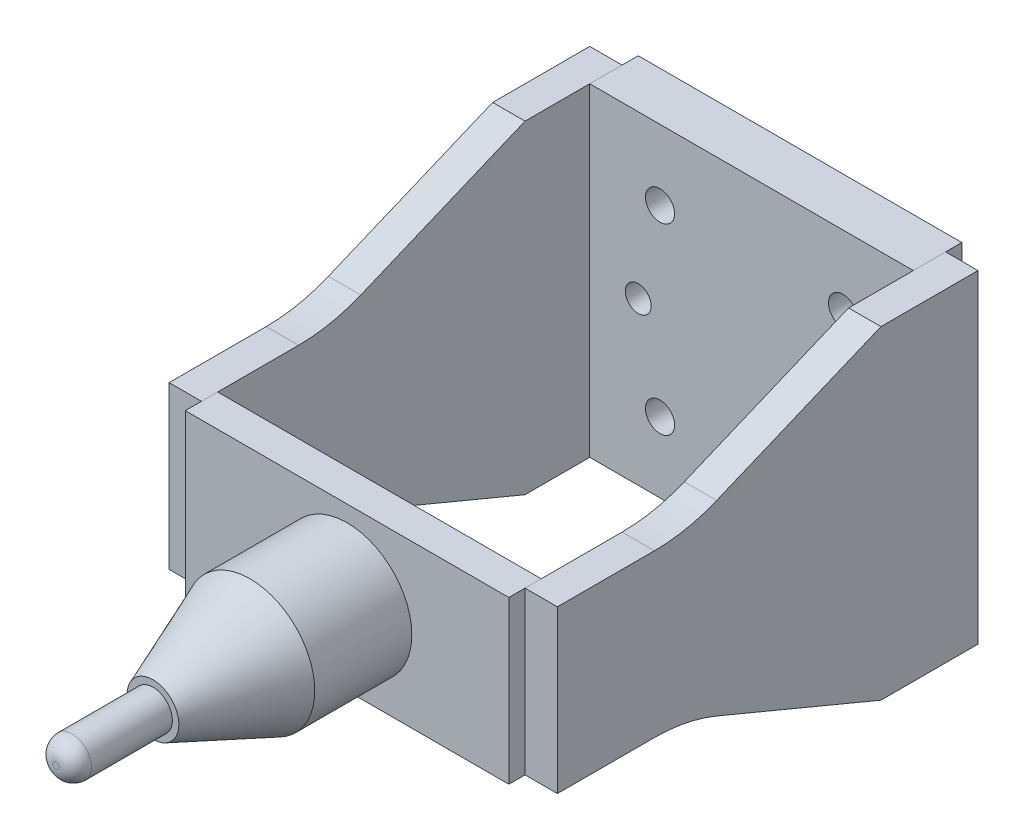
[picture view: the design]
ISO-10303-21;
HEADER;
FILE_DESCRIPTION(('STEP AP214'),'2;1');
FILE_NAME('part.step','',(''),(''),'','','');
FILE_SCHEMA(('AUTOMOTIVE_DESIGN { 1 0 10303 214 1 1 1 1 }'));
ENDSEC;
DATA;
#1=APPLICATION_CONTEXT('core data for automotive mechanical design processes');
#2=APPLICATION_PROTOCOL_DEFINITION('international standard','automotive_design',2000,#1);
#3=PRODUCT_CONTEXT('',#1,'mechanical');
#4=PRODUCT('Part','Part','',(#3));
#5=PRODUCT_RELATED_PRODUCT_CATEGORY('part','',(#4));
#6=PRODUCT_DEFINITION_FORMATION('','',#4);
#7=PRODUCT_DEFINITION_CONTEXT('part definition',#1,'design');
#8=PRODUCT_DEFINITION('design','',#6,#7);
#9=PRODUCT_DEFINITION_SHAPE('','',#8);
#10=(LENGTH_UNIT() NAMED_UNIT(*) SI_UNIT(.MILLI.,.METRE.));
#11=(NAMED_UNIT(*) PLANE_ANGLE_UNIT() SI_UNIT($,.RADIAN.));
#12=(NAMED_UNIT(*) SI_UNIT($,.STERADIAN.) SOLID_ANGLE_UNIT());
#13=UNCERTAINTY_MEASURE_WITH_UNIT(LENGTH_MEASURE(1.E-05),#10,'distance_accuracy_value','');
#14=(GEOMETRIC_REPRESENTATION_CONTEXT(3) GLOBAL_UNCERTAINTY_ASSIGNED_CONTEXT((#13)) GLOBAL_UNIT_ASSIGNED_CONTEXT((#10,
#11,#12)) REPRESENTATION_CONTEXT('',''));
#15=CARTESIAN_POINT('',(0.,0.,0.));
#16=DIRECTION('',(0.,0.,1.));
#17=DIRECTION('',(1.,0.,0.));
#18=AXIS2_PLACEMENT_3D('',#15,#16,#17);
#19=CARTESIAN_POINT('',(0.,0.,230.));
#20=DIRECTION('',(0.,0.,-1.));
#21=DIRECTION('',(-1.,0.,0.));
#22=AXIS2_PLACEMENT_3D('',#19,#20,#21);
#23=CYLINDRICAL_SURFACE('',#22,6.);
#24=CARTESIAN_POINT('',(0.,0.,225.));
#25=DIRECTION('',(0.,0.,1.));
#26=DIRECTION('',(1.,0.,0.));
#27=AXIS2_PLACEMENT_3D('',#24,#25,#26);
#28=CIRCLE('',#27,6.);
#29=CARTESIAN_POINT('',(6.,0.,225.));
#30=VERTEX_POINT('',#29);
#31=EDGE_CURVE('E11',#30,#30,#28,.F.);
#32=ORIENTED_EDGE('',*,*,#31,.T.);
#33=EDGE_LOOP('',(#32));
#34=FACE_BOUND('',#33,.T.);
#35=CARTESIAN_POINT('',(0.,0.,200.));
#36=DIRECTION('',(0.,0.,1.));
#37=DIRECTION('',(1.,0.,0.));
#38=AXIS2_PLACEMENT_3D('',#35,#36,#37);
#39=CIRCLE('',#38,6.);
#40=CARTESIAN_POINT('',(6.,0.,200.));
#41=VERTEX_POINT('',#40);
#42=EDGE_CURVE('E52',#41,#41,#39,.T.);
#43=ORIENTED_EDGE('',*,*,#42,.T.);
#44=EDGE_LOOP('',(#43));
#45=FACE_BOUND('',#44,.T.);
#46=ADVANCED_FACE('F41',(#34,#45),#23,.T.);
#47=CARTESIAN_POINT('',(0.,0.,230.));
#48=DIRECTION('',(0.,0.,1.));
#49=DIRECTION('',(1.,0.,0.));
#50=AXIS2_PLACEMENT_3D('',#47,#48,#49);
#51=PLANE('',#50);
#52=CARTESIAN_POINT('',(0.,0.,230.));
#53=DIRECTION('',(0.,0.,1.));
#54=DIRECTION('',(1.,0.,0.));
#55=AXIS2_PLACEMENT_3D('',#52,#53,#54);
#56=CIRCLE('',#55,1.);
#57=CARTESIAN_POINT('',(1.,0.,230.));
#58=VERTEX_POINT('',#57);
#59=EDGE_CURVE('E48',#58,#58,#56,.T.);
#60=ORIENTED_EDGE('',*,*,#59,.T.);
#61=EDGE_LOOP('',(#60));
#62=FACE_BOUND('',#61,.T.);
#63=ADVANCED_FACE('F62',(#62),#51,.T.);
#64=CARTESIAN_POINT('',(0.,0.,200.));
#65=DIRECTION('',(0.,0.,1.));
#66=DIRECTION('',(1.,0.,0.));
#67=AXIS2_PLACEMENT_3D('',#64,#65,#66);
#68=PLANE('',#67);
#69=ORIENTED_EDGE('',*,*,#42,.F.);
#70=EDGE_LOOP('',(#69));
#71=FACE_BOUND('',#70,.T.);
#72=ADVANCED_FACE('F60',(#71),#68,.F.);
#73=CARTESIAN_POINT('',(0.,0.,225.));
#74=DIRECTION('',(0.,0.,1.));
#75=DIRECTION('',(1.,0.,0.));
#76=AXIS2_PLACEMENT_3D('',#73,#74,#75);
#77=DEGENERATE_TOROIDAL_SURFACE('',#76,1.,5.,.T.);
#78=ORIENTED_EDGE('',*,*,#31,.F.);
#79=EDGE_LOOP('',(#78));
#80=FACE_BOUND('',#79,.T.);
#81=ORIENTED_EDGE('',*,*,#59,.F.);
#82=EDGE_LOOP('',(#81));
#83=FACE_BOUND('',#82,.T.);
#84=ADVANCED_FACE('F43',(#80,#83),#77,.T.);
#85=CLOSED_SHELL('',(#46,#63,#72,#84));
#86=MANIFOLD_SOLID_BREP('B2',#85);
#87=CARTESIAN_POINT('',(0.,0.,140.));
#88=DIRECTION('',(0.,0.,1.));
#89=DIRECTION('',(1.,0.,0.));
#90=AXIS2_PLACEMENT_3D('',#87,#88,#89);
#91=CYLINDRICAL_SURFACE('',#90,20.);
#92=CARTESIAN_POINT('',(0.,0.,170.));
#93=DIRECTION('',(0.,0.,1.));
#94=DIRECTION('',(1.,0.,0.));
#95=AXIS2_PLACEMENT_3D('',#92,#93,#94);
#96=CIRCLE('',#95,20.);
#97=CARTESIAN_POINT('',(20.,0.,170.));
#98=VERTEX_POINT('',#97);
#99=EDGE_CURVE('E127',#98,#98,#96,.T.);
#100=ORIENTED_EDGE('',*,*,#99,.F.);
#101=EDGE_LOOP('',(#100));
#102=FACE_BOUND('',#101,.T.);
#103=CARTESIAN_POINT('',(0.,0.,140.));
#104=DIRECTION('',(0.,0.,1.));
#105=DIRECTION('',(1.,0.,0.));
#106=AXIS2_PLACEMENT_3D('',#103,#104,#105);
#107=CIRCLE('',#106,20.);
#108=CARTESIAN_POINT('',(20.,0.,140.));
#109=VERTEX_POINT('',#108);
#110=EDGE_CURVE('E39',#109,#109,#107,.T.);
#111=ORIENTED_EDGE('',*,*,#110,.T.);
#112=EDGE_LOOP('',(#111));
#113=FACE_BOUND('',#112,.T.);
#114=ADVANCED_FACE('F106',(#102,#113),#91,.T.);
#115=CARTESIAN_POINT('',(0.,20.,140.));
#116=DIRECTION('',(0.,0.,1.));
#117=DIRECTION('',(1.,0.,0.));
#118=AXIS2_PLACEMENT_3D('',#115,#116,#117);
#119=PLANE('',#118);
#120=CARTESIAN_POINT('',(0.,0.,140.));
#121=DIRECTION('',(0.,0.,1.));
#122=DIRECTION('',(1.,0.,0.));
#123=AXIS2_PLACEMENT_3D('',#120,#121,#122);
#124=CIRCLE('',#123,4.99999999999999);
#125=CARTESIAN_POINT('',(4.99999999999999,0.,140.));
#126=VERTEX_POINT('',#125);
#127=EDGE_CURVE('E109',#126,#126,#124,.T.);
#128=ORIENTED_EDGE('',*,*,#127,.T.);
#129=EDGE_LOOP('',(#128));
#130=FACE_BOUND('',#129,.T.);
#131=ORIENTED_EDGE('',*,*,#110,.F.);
#132=EDGE_LOOP('',(#131));
#133=FACE_BOUND('',#132,.T.);
#134=ADVANCED_FACE('F144',(#130,#133),#119,.F.);
#135=CARTESIAN_POINT('',(0.,0.,200.));
#136=DIRECTION('',(0.,0.,-1.));
#137=DIRECTION('',(-1.,0.,0.));
#138=AXIS2_PLACEMENT_3D('',#135,#136,#137);
#139=PLANE('',#138);
#140=CARTESIAN_POINT('',(0.,0.,200.));
#141=DIRECTION('',(0.,0.,1.));
#142=DIRECTION('',(1.,0.,0.));
#143=AXIS2_PLACEMENT_3D('',#140,#141,#142);
#144=CIRCLE('',#143,8.);
#145=CARTESIAN_POINT('',(8.,0.,200.));
#146=VERTEX_POINT('',#145);
#147=EDGE_CURVE('E113',#146,#146,#144,.T.);
#148=ORIENTED_EDGE('',*,*,#147,.T.);
#149=EDGE_LOOP('',(#148));
#150=FACE_BOUND('',#149,.T.);
#151=ADVANCED_FACE('F134',(#150),#139,.F.);
#152=CARTESIAN_POINT('',(0.,0.,170.));
#153=DIRECTION('',(0.,0.,-1.));
#154=DIRECTION('',(-1.,0.,0.));
#155=AXIS2_PLACEMENT_3D('',#152,#153,#154);
#156=CONICAL_SURFACE('',#155,20.,0.380506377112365);
#157=ORIENTED_EDGE('',*,*,#147,.F.);
#158=EDGE_LOOP('',(#157));
#159=FACE_BOUND('',#158,.T.);
#160=ORIENTED_EDGE('',*,*,#99,.T.);
#161=EDGE_LOOP('',(#160));
#162=FACE_BOUND('',#161,.T.);
#163=ADVANCED_FACE('F136',(#159,#162),#156,.T.);
#164=CARTESIAN_POINT('',(0.,0.,130.));
#165=DIRECTION('',(0.,0.,-1.));
#166=DIRECTION('',(-1.,0.,0.));
#167=AXIS2_PLACEMENT_3D('',#164,#165,#166);
#168=CYLINDRICAL_SURFACE('',#167,4.99999999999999);
#169=CARTESIAN_POINT('',(0.,0.,160.));
#170=DIRECTION('',(0.,0.,-1.));
#171=DIRECTION('',(-1.,0.,0.));
#172=AXIS2_PLACEMENT_3D('',#169,#170,#171);
#173=CIRCLE('',#172,4.99999999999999);
#174=CARTESIAN_POINT('',(-4.99999999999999,0.,160.));
#175=VERTEX_POINT('',#174);
#176=EDGE_CURVE('E123',#175,#175,#173,.T.);
#177=ORIENTED_EDGE('',*,*,#176,.F.);
#178=EDGE_LOOP('',(#177));
#179=FACE_BOUND('',#178,.T.);
#180=ORIENTED_EDGE('',*,*,#127,.F.);
#181=EDGE_LOOP('',(#180));
#182=FACE_BOUND('',#181,.T.);
#183=ADVANCED_FACE('F119',(#179,#182),#168,.F.);
#184=CARTESIAN_POINT('',(0.,0.,160.));
#185=DIRECTION('',(0.,0.,-1.));
#186=DIRECTION('',(-1.,0.,0.));
#187=AXIS2_PLACEMENT_3D('',#184,#185,#186);
#188=CONICAL_SURFACE('',#187,4.99999999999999,1.02974425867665);
#189=CARTESIAN_POINT('',(0.,0.,163.004303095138));
#190=VERTEX_POINT('',#189);
#191=VERTEX_LOOP('',#190);
#192=FACE_BOUND('',#191,.T.);
#193=ORIENTED_EDGE('',*,*,#176,.T.);
#194=EDGE_LOOP('',(#193));
#195=FACE_BOUND('',#194,.T.);
#196=ADVANCED_FACE('F116',(#192,#195),#188,.F.);
#197=CLOSED_SHELL('',(#114,#134,#151,#163,#183,#196));
#198=MANIFOLD_SOLID_BREP('B6',#197);
#199=CARTESIAN_POINT('',(-50.,-75.,105.));
#200=DIRECTION('',(-1.,0.,0.));
#201=DIRECTION('',(0.,0.,1.));
#202=AXIS2_PLACEMENT_3D('',#199,#200,#201);
#203=PLANE('',#202);
#204=DIRECTION('',(0.,-1.,0.));
#205=VECTOR('',#204,1.);
#206=CARTESIAN_POINT('',(-50.,25.,140.));
#207=LINE('',#206,#205);
#208=CARTESIAN_POINT('',(-50.,25.,140.));
#209=VERTEX_POINT('',#208);
#210=CARTESIAN_POINT('',(-50.,-25.,140.));
#211=VERTEX_POINT('',#210);
#212=EDGE_CURVE('E211',#209,#211,#207,.T.);
#213=ORIENTED_EDGE('',*,*,#212,.F.);
#214=DIRECTION('',(0.,0.,1.));
#215=VECTOR('',#214,1.);
#216=CARTESIAN_POINT('',(-50.,25.,140.));
#217=LINE('',#216,#215);
#218=CARTESIAN_POINT('',(-50.,25.,130.));
#219=VERTEX_POINT('',#218);
#220=EDGE_CURVE('E256',#219,#209,#217,.T.);
#221=ORIENTED_EDGE('',*,*,#220,.F.);
#222=DIRECTION('',(0.,1.,0.));
#223=VECTOR('',#222,1.);
#224=CARTESIAN_POINT('',(-50.,25.,130.));
#225=LINE('',#224,#223);
#226=CARTESIAN_POINT('',(-50.,-25.,130.));
#227=VERTEX_POINT('',#226);
#228=EDGE_CURVE('E224',#227,#219,#225,.T.);
#229=ORIENTED_EDGE('',*,*,#228,.F.);
#230=DIRECTION('',(0.,0.,-1.));
#231=VECTOR('',#230,1.);
#232=CARTESIAN_POINT('',(-50.,-25.,140.));
#233=LINE('',#232,#231);
#234=EDGE_CURVE('E218',#211,#227,#233,.T.);
#235=ORIENTED_EDGE('',*,*,#234,.F.);
#236=EDGE_LOOP('',(#213,#221,#229,#235));
#237=FACE_BOUND('',#236,.T.);
#238=ADVANCED_FACE('F204',(#237),#203,.T.);
#239=CARTESIAN_POINT('',(-100.990195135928,-25.,140.));
#240=DIRECTION('',(0.,-1.,0.));
#241=DIRECTION('',(0.,0.,-1.));
#242=AXIS2_PLACEMENT_3D('',#239,#240,#241);
#243=PLANE('',#242);
#244=DIRECTION('',(1.,0.,0.));
#245=VECTOR('',#244,1.);
#246=CARTESIAN_POINT('',(-100.990195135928,-25.,140.));
#247=LINE('',#246,#245);
#248=CARTESIAN_POINT('',(50.,-25.,140.));
#249=VERTEX_POINT('',#248);
#250=EDGE_CURVE('E104',#211,#249,#247,.T.);
#251=ORIENTED_EDGE('',*,*,#250,.F.);
#252=ORIENTED_EDGE('',*,*,#234,.T.);
#253=DIRECTION('',(1.,0.,0.));
#254=VECTOR('',#253,1.);
#255=CARTESIAN_POINT('',(-100.990195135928,-25.,130.));
#256=LINE('',#255,#254);
#257=CARTESIAN_POINT('',(50.,-25.,130.));
#258=VERTEX_POINT('',#257);
#259=EDGE_CURVE('E236',#227,#258,#256,.T.);
#260=ORIENTED_EDGE('',*,*,#259,.T.);
#261=DIRECTION('',(0.,0.,1.));
#262=VECTOR('',#261,1.);
#263=CARTESIAN_POINT('',(50.,-25.,140.));
#264=LINE('',#263,#262);
#265=EDGE_CURVE('E263',#258,#249,#264,.T.);
#266=ORIENTED_EDGE('',*,*,#265,.T.);
#267=EDGE_LOOP('',(#251,#252,#260,#266));
#268=FACE_BOUND('',#267,.T.);
#269=ADVANCED_FACE('F280',(#268),#243,.T.);
#270=CARTESIAN_POINT('',(-100.990195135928,25.,130.));
#271=DIRECTION('',(0.,0.,-1.));
#272=DIRECTION('',(-1.,0.,0.));
#273=AXIS2_PLACEMENT_3D('',#270,#271,#272);
#274=PLANE('',#273);
#275=CARTESIAN_POINT('',(0.,0.,130.));
#276=DIRECTION('',(0.,0.,-1.));
#277=DIRECTION('',(-1.,0.,0.));
#278=AXIS2_PLACEMENT_3D('',#275,#276,#277);
#279=CIRCLE('',#278,5.);
#280=CARTESIAN_POINT('',(-5.,0.,130.));
#281=VERTEX_POINT('',#280);
#282=EDGE_CURVE('E269',#281,#281,#279,.T.);
#283=ORIENTED_EDGE('',*,*,#282,.F.);
#284=EDGE_LOOP('',(#283));
#285=FACE_BOUND('',#284,.T.);
#286=ORIENTED_EDGE('',*,*,#259,.F.);
#287=ORIENTED_EDGE('',*,*,#228,.T.);
#288=DIRECTION('',(1.,0.,0.));
#289=VECTOR('',#288,1.);
#290=CARTESIAN_POINT('',(-100.990195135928,25.,130.));
#291=LINE('',#290,#289);
#292=CARTESIAN_POINT('',(50.,25.,130.));
#293=VERTEX_POINT('',#292);
#294=EDGE_CURVE('E252',#219,#293,#291,.T.);
#295=ORIENTED_EDGE('',*,*,#294,.T.);
#296=DIRECTION('',(0.,-1.,0.));
#297=VECTOR('',#296,1.);
#298=CARTESIAN_POINT('',(50.,25.,130.));
#299=LINE('',#298,#297);
#300=EDGE_CURVE('E255',#293,#258,#299,.T.);
#301=ORIENTED_EDGE('',*,*,#300,.T.);
#302=EDGE_LOOP('',(#286,#287,#295,#301));
#303=FACE_BOUND('',#302,.T.);
#304=ADVANCED_FACE('F254',(#285,#303),#274,.T.);
#305=CARTESIAN_POINT('',(-100.990195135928,25.,140.));
#306=DIRECTION('',(0.,1.,0.));
#307=DIRECTION('',(0.,0.,1.));
#308=AXIS2_PLACEMENT_3D('',#305,#306,#307);
#309=PLANE('',#308);
#310=ORIENTED_EDGE('',*,*,#294,.F.);
#311=ORIENTED_EDGE('',*,*,#220,.T.);
#312=DIRECTION('',(1.,0.,0.));
#313=VECTOR('',#312,1.);
#314=CARTESIAN_POINT('',(-100.990195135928,25.,140.));
#315=LINE('',#314,#313);
#316=CARTESIAN_POINT('',(50.,25.,140.));
#317=VERTEX_POINT('',#316);
#318=EDGE_CURVE('E243',#209,#317,#315,.T.);
#319=ORIENTED_EDGE('',*,*,#318,.T.);
#320=DIRECTION('',(0.,0.,-1.));
#321=VECTOR('',#320,1.);
#322=CARTESIAN_POINT('',(50.,25.,140.));
#323=LINE('',#322,#321);
#324=EDGE_CURVE('E261',#317,#293,#323,.T.);
#325=ORIENTED_EDGE('',*,*,#324,.T.);
#326=EDGE_LOOP('',(#310,#311,#319,#325));
#327=FACE_BOUND('',#326,.T.);
#328=ADVANCED_FACE('F265',(#327),#309,.T.);
#329=CARTESIAN_POINT('',(-100.990195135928,25.,140.));
#330=DIRECTION('',(0.,0.,1.));
#331=DIRECTION('',(1.,0.,0.));
#332=AXIS2_PLACEMENT_3D('',#329,#330,#331);
#333=PLANE('',#332);
#334=CARTESIAN_POINT('',(0.,0.,140.));
#335=DIRECTION('',(0.,0.,1.));
#336=DIRECTION('',(1.,0.,0.));
#337=AXIS2_PLACEMENT_3D('',#334,#335,#336);
#338=CIRCLE('',#337,4.99999999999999);
#339=CARTESIAN_POINT('',(4.99999999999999,0.,140.));
#340=VERTEX_POINT('',#339);
#341=EDGE_CURVE('E266',#340,#340,#338,.T.);
#342=ORIENTED_EDGE('',*,*,#341,.F.);
#343=EDGE_LOOP('',(#342));
#344=FACE_BOUND('',#343,.T.);
#345=ORIENTED_EDGE('',*,*,#318,.F.);
#346=ORIENTED_EDGE('',*,*,#212,.T.);
#347=ORIENTED_EDGE('',*,*,#250,.T.);
#348=DIRECTION('',(0.,1.,0.));
#349=VECTOR('',#348,1.);
#350=CARTESIAN_POINT('',(50.,25.,140.));
#351=LINE('',#350,#349);
#352=EDGE_CURVE('E273',#249,#317,#351,.T.);
#353=ORIENTED_EDGE('',*,*,#352,.T.);
#354=EDGE_LOOP('',(#345,#346,#347,#353));
#355=FACE_BOUND('',#354,.T.);
#356=ADVANCED_FACE('F293',(#344,#355),#333,.T.);
#357=CARTESIAN_POINT('',(50.,0.,0.));
#358=DIRECTION('',(-1.,0.,0.));
#359=DIRECTION('',(0.,0.,1.));
#360=AXIS2_PLACEMENT_3D('',#357,#358,#359);
#361=PLANE('',#360);
#362=ORIENTED_EDGE('',*,*,#265,.F.);
#363=ORIENTED_EDGE('',*,*,#300,.F.);
#364=ORIENTED_EDGE('',*,*,#324,.F.);
#365=ORIENTED_EDGE('',*,*,#352,.F.);
#366=EDGE_LOOP('',(#362,#363,#364,#365));
#367=FACE_BOUND('',#366,.T.);
#368=ADVANCED_FACE('F259',(#367),#361,.F.);
#369=CARTESIAN_POINT('',(0.,0.,130.));
#370=DIRECTION('',(0.,0.,-1.));
#371=DIRECTION('',(-1.,0.,0.));
#372=AXIS2_PLACEMENT_3D('',#369,#370,#371);
#373=CYLINDRICAL_SURFACE('',#372,4.99999999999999);
#374=ORIENTED_EDGE('',*,*,#341,.T.);
#375=EDGE_LOOP('',(#374));
#376=FACE_BOUND('',#375,.T.);
#377=ORIENTED_EDGE('',*,*,#282,.T.);
#378=EDGE_LOOP('',(#377));
#379=FACE_BOUND('',#378,.T.);
#380=ADVANCED_FACE('F299',(#376,#379),#373,.F.);
#381=CLOSED_SHELL('',(#238,#269,#304,#328,#356,#368,#380));
#382=MANIFOLD_SOLID_BREP('B33',#381);
#383=CARTESIAN_POINT('',(-60.,28.8461538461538,85.7692307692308));
#384=DIRECTION('',(0.,-0.923076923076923,-0.384615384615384));
#385=DIRECTION('',(0.,0.384615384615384,-0.923076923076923));
#386=AXIS2_PLACEMENT_3D('',#383,#384,#385);
#387=PLANE('',#386);
#388=DIRECTION('',(0.,0.384615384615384,-0.923076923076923));
#389=VECTOR('',#388,1.);
#390=CARTESIAN_POINT('',(-50.,28.8461538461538,85.7692307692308));
#391=LINE('',#390,#389);
#392=CARTESIAN_POINT('',(-50.,28.8461538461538,85.7692307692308));
#393=VERTEX_POINT('',#392);
#394=CARTESIAN_POINT('',(-50.,50.,35.));
#395=VERTEX_POINT('',#394);
#396=EDGE_CURVE('E466',#393,#395,#391,.T.);
#397=ORIENTED_EDGE('',*,*,#396,.T.);
#398=DIRECTION('',(1.,0.,0.));
#399=VECTOR('',#398,1.);
#400=CARTESIAN_POINT('',(-60.,50.,35.));
#401=LINE('',#400,#399);
#402=CARTESIAN_POINT('',(-60.,50.,35.));
#403=VERTEX_POINT('',#402);
#404=EDGE_CURVE('E202',#403,#395,#401,.T.);
#405=ORIENTED_EDGE('',*,*,#404,.F.);
#406=DIRECTION('',(0.,0.384615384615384,-0.923076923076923));
#407=VECTOR('',#406,1.);
#408=CARTESIAN_POINT('',(-60.,28.8461538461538,85.7692307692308));
#409=LINE('',#408,#407);
#410=CARTESIAN_POINT('',(-60.,28.8461538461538,85.7692307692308));
#411=VERTEX_POINT('',#410);
#412=EDGE_CURVE('E484',#411,#403,#409,.T.);
#413=ORIENTED_EDGE('',*,*,#412,.F.);
#414=DIRECTION('',(1.,0.,0.));
#415=VECTOR('',#414,1.);
#416=CARTESIAN_POINT('',(-60.,28.8461538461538,85.7692307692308));
#417=LINE('',#416,#415);
#418=EDGE_CURVE('E462',#411,#393,#417,.T.);
#419=ORIENTED_EDGE('',*,*,#418,.T.);
#420=EDGE_LOOP('',(#397,#405,#413,#419));
#421=FACE_BOUND('',#420,.T.);
#422=ADVANCED_FACE('F358',(#421),#387,.F.);
#423=CARTESIAN_POINT('',(-60.,50.,35.));
#424=DIRECTION('',(0.,-1.,0.));
#425=DIRECTION('',(0.,0.,-1.));
#426=AXIS2_PLACEMENT_3D('',#423,#424,#425);
#427=PLANE('',#426);
#428=DIRECTION('',(0.,0.,-1.));
#429=VECTOR('',#428,1.);
#430=CARTESIAN_POINT('',(-50.,50.,35.));
#431=LINE('',#430,#429);
#432=CARTESIAN_POINT('',(-50.,50.,4.99999999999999));
#433=VERTEX_POINT('',#432);
#434=EDGE_CURVE('E469',#395,#433,#431,.T.);
#435=ORIENTED_EDGE('',*,*,#434,.T.);
#436=DIRECTION('',(1.,0.,0.));
#437=VECTOR('',#436,1.);
#438=CARTESIAN_POINT('',(-60.,50.,4.99999999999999));
#439=LINE('',#438,#437);
#440=CARTESIAN_POINT('',(-60.,50.,4.99999999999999));
#441=VERTEX_POINT('',#440);
#442=EDGE_CURVE('E366',#441,#433,#439,.T.);
#443=ORIENTED_EDGE('',*,*,#442,.F.);
#444=DIRECTION('',(0.,0.,-1.));
#445=VECTOR('',#444,1.);
#446=CARTESIAN_POINT('',(-60.,50.,35.));
#447=LINE('',#446,#445);
#448=EDGE_CURVE('E423',#403,#441,#447,.T.);
#449=ORIENTED_EDGE('',*,*,#448,.F.);
#450=ORIENTED_EDGE('',*,*,#404,.T.);
#451=EDGE_LOOP('',(#435,#443,#449,#450));
#452=FACE_BOUND('',#451,.T.);
#453=ADVANCED_FACE('F533',(#452),#427,.F.);
#454=CARTESIAN_POINT('',(-60.,50.,4.99999999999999));
#455=DIRECTION('',(0.,0.,1.));
#456=DIRECTION('',(0.,-1.,0.));
#457=AXIS2_PLACEMENT_3D('',#454,#455,#456);
#458=PLANE('',#457);
#459=DIRECTION('',(0.,-1.,0.));
#460=VECTOR('',#459,1.);
#461=CARTESIAN_POINT('',(-50.,50.,4.99999999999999));
#462=LINE('',#461,#460);
#463=CARTESIAN_POINT('',(-50.,-50.,4.99999999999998));
#464=VERTEX_POINT('',#463);
#465=EDGE_CURVE('E471',#433,#464,#462,.T.);
#466=ORIENTED_EDGE('',*,*,#465,.T.);
#467=DIRECTION('',(1.,0.,0.));
#468=VECTOR('',#467,1.);
#469=CARTESIAN_POINT('',(-60.,-50.,4.99999999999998));
#470=LINE('',#469,#468);
#471=CARTESIAN_POINT('',(-60.,-50.,4.99999999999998));
#472=VERTEX_POINT('',#471);
#473=EDGE_CURVE('E497',#472,#464,#470,.T.);
#474=ORIENTED_EDGE('',*,*,#473,.F.);
#475=DIRECTION('',(0.,-1.,0.));
#476=VECTOR('',#475,1.);
#477=CARTESIAN_POINT('',(-60.,50.,4.99999999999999));
#478=LINE('',#477,#476);
#479=EDGE_CURVE('E505',#441,#472,#478,.T.);
#480=ORIENTED_EDGE('',*,*,#479,.F.);
#481=ORIENTED_EDGE('',*,*,#442,.T.);
#482=EDGE_LOOP('',(#466,#474,#480,#481));
#483=FACE_BOUND('',#482,.T.);
#484=ADVANCED_FACE('F503',(#483),#458,.F.);
#485=CARTESIAN_POINT('',(-60.,-50.,4.99999999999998));
#486=DIRECTION('',(0.,1.,0.));
#487=DIRECTION('',(0.,0.,1.));
#488=AXIS2_PLACEMENT_3D('',#485,#486,#487);
#489=PLANE('',#488);
#490=DIRECTION('',(0.,0.,1.));
#491=VECTOR('',#490,1.);
#492=CARTESIAN_POINT('',(-50.,-50.,4.99999999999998));
#493=LINE('',#492,#491);
#494=CARTESIAN_POINT('',(-50.,-50.,35.));
#495=VERTEX_POINT('',#494);
#496=EDGE_CURVE('E473',#464,#495,#493,.T.);
#497=ORIENTED_EDGE('',*,*,#496,.T.);
#498=DIRECTION('',(1.,0.,0.));
#499=VECTOR('',#498,1.);
#500=CARTESIAN_POINT('',(-60.,-50.,35.));
#501=LINE('',#500,#499);
#502=CARTESIAN_POINT('',(-60.,-50.,35.));
#503=VERTEX_POINT('',#502);
#504=EDGE_CURVE('E494',#503,#495,#501,.T.);
#505=ORIENTED_EDGE('',*,*,#504,.F.);
#506=DIRECTION('',(0.,0.,1.));
#507=VECTOR('',#506,1.);
#508=CARTESIAN_POINT('',(-60.,-50.,4.99999999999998));
#509=LINE('',#508,#507);
#510=EDGE_CURVE('E523',#472,#503,#509,.T.);
#511=ORIENTED_EDGE('',*,*,#510,.F.);
#512=ORIENTED_EDGE('',*,*,#473,.T.);
#513=EDGE_LOOP('',(#497,#505,#511,#512));
#514=FACE_BOUND('',#513,.T.);
#515=ADVANCED_FACE('F514',(#514),#489,.F.);
#516=CARTESIAN_POINT('',(-60.,-50.,35.));
#517=DIRECTION('',(0.,0.923076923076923,-0.384615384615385));
#518=DIRECTION('',(0.,0.384615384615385,0.923076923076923));
#519=AXIS2_PLACEMENT_3D('',#516,#517,#518);
#520=PLANE('',#519);
#521=DIRECTION('',(0.,0.384615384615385,0.923076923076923));
#522=VECTOR('',#521,1.);
#523=CARTESIAN_POINT('',(-50.,-50.,35.));
#524=LINE('',#523,#522);
#525=CARTESIAN_POINT('',(-50.,-28.8461538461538,85.7692307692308));
#526=VERTEX_POINT('',#525);
#527=EDGE_CURVE('E475',#495,#526,#524,.T.);
#528=ORIENTED_EDGE('',*,*,#527,.T.);
#529=DIRECTION('',(1.,0.,0.));
#530=VECTOR('',#529,1.);
#531=CARTESIAN_POINT('',(-60.,-28.8461538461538,85.7692307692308));
#532=LINE('',#531,#530);
#533=CARTESIAN_POINT('',(-60.,-28.8461538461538,85.7692307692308));
#534=VERTEX_POINT('',#533);
#535=EDGE_CURVE('E491',#534,#526,#532,.T.);
#536=ORIENTED_EDGE('',*,*,#535,.F.);
#537=DIRECTION('',(0.,0.384615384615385,0.923076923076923));
#538=VECTOR('',#537,1.);
#539=CARTESIAN_POINT('',(-60.,-50.,35.));
#540=LINE('',#539,#538);
#541=EDGE_CURVE('E520',#503,#534,#540,.T.);
#542=ORIENTED_EDGE('',*,*,#541,.F.);
#543=ORIENTED_EDGE('',*,*,#504,.T.);
#544=EDGE_LOOP('',(#528,#536,#542,#543));
#545=FACE_BOUND('',#544,.T.);
#546=ADVANCED_FACE('F518',(#545),#520,.F.);
#547=CARTESIAN_POINT('',(-60.,-75.,105.));
#548=DIRECTION('',(1.,0.,0.));
#549=DIRECTION('',(0.,0.,-1.));
#550=AXIS2_PLACEMENT_3D('',#547,#548,#549);
#551=CYLINDRICAL_SURFACE('',#550,50.);
#552=CARTESIAN_POINT('',(-50.,-75.,105.));
#553=DIRECTION('',(1.,0.,0.));
#554=DIRECTION('',(0.,0.,1.));
#555=AXIS2_PLACEMENT_3D('',#552,#553,#554);
#556=CIRCLE('',#555,50.);
#557=CARTESIAN_POINT('',(-50.,-25.,105.));
#558=VERTEX_POINT('',#557);
#559=EDGE_CURVE('E477',#526,#558,#556,.T.);
#560=ORIENTED_EDGE('',*,*,#559,.T.);
#561=DIRECTION('',(1.,0.,0.));
#562=VECTOR('',#561,1.);
#563=CARTESIAN_POINT('',(-60.,-25.,105.));
#564=LINE('',#563,#562);
#565=CARTESIAN_POINT('',(-60.,-25.,105.));
#566=VERTEX_POINT('',#565);
#567=EDGE_CURVE('E488',#566,#558,#564,.T.);
#568=ORIENTED_EDGE('',*,*,#567,.F.);
#569=CARTESIAN_POINT('',(-60.,-75.,105.));
#570=DIRECTION('',(1.,0.,0.));
#571=DIRECTION('',(0.,0.,1.));
#572=AXIS2_PLACEMENT_3D('',#569,#570,#571);
#573=CIRCLE('',#572,50.);
#574=EDGE_CURVE('E522',#534,#566,#573,.T.);
#575=ORIENTED_EDGE('',*,*,#574,.F.);
#576=ORIENTED_EDGE('',*,*,#535,.T.);
#577=EDGE_LOOP('',(#560,#568,#575,#576));
#578=FACE_BOUND('',#577,.T.);
#579=ADVANCED_FACE('F545',(#578),#551,.F.);
#580=CARTESIAN_POINT('',(-60.,-25.,105.));
#581=DIRECTION('',(0.,1.,0.));
#582=DIRECTION('',(0.,0.,1.));
#583=AXIS2_PLACEMENT_3D('',#580,#581,#582);
#584=PLANE('',#583);
#585=DIRECTION('',(0.,0.,1.));
#586=VECTOR('',#585,1.);
#587=CARTESIAN_POINT('',(-50.,-25.,105.));
#588=LINE('',#587,#586);
#589=CARTESIAN_POINT('',(-50.,-25.,135.));
#590=VERTEX_POINT('',#589);
#591=EDGE_CURVE('E479',#558,#590,#588,.T.);
#592=ORIENTED_EDGE('',*,*,#591,.T.);
#593=DIRECTION('',(1.,0.,0.));
#594=VECTOR('',#593,1.);
#595=CARTESIAN_POINT('',(-60.,-25.,135.));
#596=LINE('',#595,#594);
#597=CARTESIAN_POINT('',(-60.,-25.,135.));
#598=VERTEX_POINT('',#597);
#599=EDGE_CURVE('E457',#598,#590,#596,.T.);
#600=ORIENTED_EDGE('',*,*,#599,.F.);
#601=DIRECTION('',(0.,0.,1.));
#602=VECTOR('',#601,1.);
#603=CARTESIAN_POINT('',(-60.,-25.,105.));
#604=LINE('',#603,#602);
#605=EDGE_CURVE('E448',#566,#598,#604,.T.);
#606=ORIENTED_EDGE('',*,*,#605,.F.);
#607=ORIENTED_EDGE('',*,*,#567,.T.);
#608=EDGE_LOOP('',(#592,#600,#606,#607));
#609=FACE_BOUND('',#608,.T.);
#610=ADVANCED_FACE('F548',(#609),#584,.F.);
#611=CARTESIAN_POINT('',(-60.,-25.,135.));
#612=DIRECTION('',(0.,0.,-1.));
#613=DIRECTION('',(-1.,0.,0.));
#614=AXIS2_PLACEMENT_3D('',#611,#612,#613);
#615=PLANE('',#614);
#616=DIRECTION('',(0.,1.,0.));
#617=VECTOR('',#616,1.);
#618=CARTESIAN_POINT('',(-50.,-25.,135.));
#619=LINE('',#618,#617);
#620=CARTESIAN_POINT('',(-50.,25.,135.));
#621=VERTEX_POINT('',#620);
#622=EDGE_CURVE('E456',#590,#621,#619,.T.);
#623=ORIENTED_EDGE('',*,*,#622,.T.);
#624=DIRECTION('',(1.,0.,0.));
#625=VECTOR('',#624,1.);
#626=CARTESIAN_POINT('',(-60.,25.,135.));
#627=LINE('',#626,#625);
#628=CARTESIAN_POINT('',(-60.,25.,135.));
#629=VERTEX_POINT('',#628);
#630=EDGE_CURVE('E453',#629,#621,#627,.T.);
#631=ORIENTED_EDGE('',*,*,#630,.F.);
#632=DIRECTION('',(0.,1.,0.));
#633=VECTOR('',#632,1.);
#634=CARTESIAN_POINT('',(-60.,-25.,135.));
#635=LINE('',#634,#633);
#636=EDGE_CURVE('E442',#598,#629,#635,.T.);
#637=ORIENTED_EDGE('',*,*,#636,.F.);
#638=ORIENTED_EDGE('',*,*,#599,.T.);
#639=EDGE_LOOP('',(#623,#631,#637,#638));
#640=FACE_BOUND('',#639,.T.);
#641=ADVANCED_FACE('F454',(#640),#615,.F.);
#642=CARTESIAN_POINT('',(-60.,25.,135.));
#643=DIRECTION('',(0.,-1.,0.));
#644=DIRECTION('',(0.,0.,-1.));
#645=AXIS2_PLACEMENT_3D('',#642,#643,#644);
#646=PLANE('',#645);
#647=DIRECTION('',(0.,0.,-1.));
#648=VECTOR('',#647,1.);
#649=CARTESIAN_POINT('',(-50.,25.,135.));
#650=LINE('',#649,#648);
#651=CARTESIAN_POINT('',(-50.,25.,105.));
#652=VERTEX_POINT('',#651);
#653=EDGE_CURVE('E409',#621,#652,#650,.T.);
#654=ORIENTED_EDGE('',*,*,#653,.T.);
#655=DIRECTION('',(1.,0.,0.));
#656=VECTOR('',#655,1.);
#657=CARTESIAN_POINT('',(-60.,25.,105.));
#658=LINE('',#657,#656);
#659=CARTESIAN_POINT('',(-60.,25.,105.));
#660=VERTEX_POINT('',#659);
#661=EDGE_CURVE('E458',#660,#652,#658,.T.);
#662=ORIENTED_EDGE('',*,*,#661,.F.);
#663=DIRECTION('',(0.,0.,-1.));
#664=VECTOR('',#663,1.);
#665=CARTESIAN_POINT('',(-60.,25.,135.));
#666=LINE('',#665,#664);
#667=EDGE_CURVE('E446',#629,#660,#666,.T.);
#668=ORIENTED_EDGE('',*,*,#667,.F.);
#669=ORIENTED_EDGE('',*,*,#630,.T.);
#670=EDGE_LOOP('',(#654,#662,#668,#669));
#671=FACE_BOUND('',#670,.T.);
#672=ADVANCED_FACE('F460',(#671),#646,.F.);
#673=CARTESIAN_POINT('',(-60.,75.,105.));
#674=DIRECTION('',(1.,0.,0.));
#675=DIRECTION('',(0.,0.,-1.));
#676=AXIS2_PLACEMENT_3D('',#673,#674,#675);
#677=CYLINDRICAL_SURFACE('',#676,50.);
#678=CARTESIAN_POINT('',(-50.,75.,105.));
#679=DIRECTION('',(1.,0.,0.));
#680=DIRECTION('',(0.,0.,1.));
#681=AXIS2_PLACEMENT_3D('',#678,#679,#680);
#682=CIRCLE('',#681,50.);
#683=EDGE_CURVE('E415',#652,#393,#682,.T.);
#684=ORIENTED_EDGE('',*,*,#683,.T.);
#685=ORIENTED_EDGE('',*,*,#418,.F.);
#686=CARTESIAN_POINT('',(-60.,75.,105.));
#687=DIRECTION('',(1.,0.,0.));
#688=DIRECTION('',(0.,0.,1.));
#689=AXIS2_PLACEMENT_3D('',#686,#687,#688);
#690=CIRCLE('',#689,50.);
#691=EDGE_CURVE('E374',#660,#411,#690,.T.);
#692=ORIENTED_EDGE('',*,*,#691,.F.);
#693=ORIENTED_EDGE('',*,*,#661,.T.);
#694=EDGE_LOOP('',(#684,#685,#692,#693));
#695=FACE_BOUND('',#694,.T.);
#696=ADVANCED_FACE('F557',(#695),#677,.F.);
#697=CARTESIAN_POINT('',(-60.,-75.,105.));
#698=DIRECTION('',(-1.,0.,0.));
#699=DIRECTION('',(0.,0.,1.));
#700=AXIS2_PLACEMENT_3D('',#697,#698,#699);
#701=PLANE('',#700);
#702=ORIENTED_EDGE('',*,*,#412,.T.);
#703=ORIENTED_EDGE('',*,*,#448,.T.);
#704=ORIENTED_EDGE('',*,*,#479,.T.);
#705=ORIENTED_EDGE('',*,*,#510,.T.);
#706=ORIENTED_EDGE('',*,*,#541,.T.);
#707=ORIENTED_EDGE('',*,*,#574,.T.);
#708=ORIENTED_EDGE('',*,*,#605,.T.);
#709=ORIENTED_EDGE('',*,*,#636,.T.);
#710=ORIENTED_EDGE('',*,*,#667,.T.);
#711=ORIENTED_EDGE('',*,*,#691,.T.);
#712=EDGE_LOOP('',(#702,#703,#704,#705,#706,#707,#708,#709,#710,#711));
#713=FACE_BOUND('',#712,.T.);
#714=ADVANCED_FACE('F444',(#713),#701,.T.);
#715=CARTESIAN_POINT('',(-50.,-75.,105.));
#716=DIRECTION('',(-1.,0.,0.));
#717=DIRECTION('',(0.,0.,1.));
#718=AXIS2_PLACEMENT_3D('',#715,#716,#717);
#719=PLANE('',#718);
#720=ORIENTED_EDGE('',*,*,#396,.F.);
#721=ORIENTED_EDGE('',*,*,#683,.F.);
#722=ORIENTED_EDGE('',*,*,#653,.F.);
#723=ORIENTED_EDGE('',*,*,#622,.F.);
#724=ORIENTED_EDGE('',*,*,#591,.F.);
#725=ORIENTED_EDGE('',*,*,#559,.F.);
#726=ORIENTED_EDGE('',*,*,#527,.F.);
#727=ORIENTED_EDGE('',*,*,#496,.F.);
#728=ORIENTED_EDGE('',*,*,#465,.F.);
#729=ORIENTED_EDGE('',*,*,#434,.F.);
#730=EDGE_LOOP('',(#720,#721,#722,#723,#724,#725,#726,#727,#728,#729));
#731=FACE_BOUND('',#730,.T.);
#732=ADVANCED_FACE('F509',(#731),#719,.F.);
#733=CLOSED_SHELL('',(#422,#453,#484,#515,#546,#579,#610,#641,#672,#696,#714,#732));
#734=MANIFOLD_SOLID_BREP('B98',#733);
#735=CARTESIAN_POINT('',(60.,50.,35.));
#736=DIRECTION('',(0.,-1.,0.));
#737=DIRECTION('',(0.,0.,-1.));
#738=AXIS2_PLACEMENT_3D('',#735,#736,#737);
#739=PLANE('',#738);
#740=DIRECTION('',(0.,0.,1.));
#741=VECTOR('',#740,1.);
#742=CARTESIAN_POINT('',(50.,50.,35.));
#743=LINE('',#742,#741);
#744=CARTESIAN_POINT('',(50.,50.,4.99999999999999));
#745=VERTEX_POINT('',#744);
#746=CARTESIAN_POINT('',(50.,50.,35.));
#747=VERTEX_POINT('',#746);
#748=EDGE_CURVE('E740',#745,#747,#743,.T.);
#749=ORIENTED_EDGE('',*,*,#748,.T.);
#750=DIRECTION('',(-1.,0.,0.));
#751=VECTOR('',#750,1.);
#752=CARTESIAN_POINT('',(60.,50.,35.));
#753=LINE('',#752,#751);
#754=CARTESIAN_POINT('',(60.,50.,35.));
#755=VERTEX_POINT('',#754);
#756=EDGE_CURVE('E723',#755,#747,#753,.T.);
#757=ORIENTED_EDGE('',*,*,#756,.F.);
#758=DIRECTION('',(0.,0.,1.));
#759=VECTOR('',#758,1.);
#760=CARTESIAN_POINT('',(60.,50.,35.));
#761=LINE('',#760,#759);
#762=CARTESIAN_POINT('',(60.,50.,4.99999999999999));
#763=VERTEX_POINT('',#762);
#764=EDGE_CURVE('E728',#763,#755,#761,.T.);
#765=ORIENTED_EDGE('',*,*,#764,.F.);
#766=DIRECTION('',(-1.,0.,0.));
#767=VECTOR('',#766,1.);
#768=CARTESIAN_POINT('',(60.,50.,4.99999999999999));
#769=LINE('',#768,#767);
#770=EDGE_CURVE('E800',#763,#745,#769,.T.);
#771=ORIENTED_EDGE('',*,*,#770,.T.);
#772=EDGE_LOOP('',(#749,#757,#765,#771));
#773=FACE_BOUND('',#772,.T.);
#774=ADVANCED_FACE('F646',(#773),#739,.F.);
#775=CARTESIAN_POINT('',(60.,25.,95.));
#776=DIRECTION('',(0.,-0.923076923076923,-0.384615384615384));
#777=DIRECTION('',(0.,0.384615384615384,-0.923076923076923));
#778=AXIS2_PLACEMENT_3D('',#775,#776,#777);
#779=PLANE('',#778);
#780=DIRECTION('',(0.,-0.384615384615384,0.923076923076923));
#781=VECTOR('',#780,1.);
#782=CARTESIAN_POINT('',(50.,25.,95.));
#783=LINE('',#782,#781);
#784=CARTESIAN_POINT('',(50.,28.8461538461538,85.7692307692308));
#785=VERTEX_POINT('',#784);
#786=EDGE_CURVE('E815',#747,#785,#783,.T.);
#787=ORIENTED_EDGE('',*,*,#786,.T.);
#788=DIRECTION('',(-1.,0.,0.));
#789=VECTOR('',#788,1.);
#790=CARTESIAN_POINT('',(60.,28.8461538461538,85.7692307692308));
#791=LINE('',#790,#789);
#792=CARTESIAN_POINT('',(60.,28.8461538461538,85.7692307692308));
#793=VERTEX_POINT('',#792);
#794=EDGE_CURVE('E661',#785,#793,#791,.F.);
#795=ORIENTED_EDGE('',*,*,#794,.T.);
#796=DIRECTION('',(0.,-0.384615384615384,0.923076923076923));
#797=VECTOR('',#796,1.);
#798=CARTESIAN_POINT('',(60.,25.,95.));
#799=LINE('',#798,#797);
#800=EDGE_CURVE('E719',#755,#793,#799,.T.);
#801=ORIENTED_EDGE('',*,*,#800,.F.);
#802=ORIENTED_EDGE('',*,*,#756,.T.);
#803=EDGE_LOOP('',(#787,#795,#801,#802));
#804=FACE_BOUND('',#803,.T.);
#805=ADVANCED_FACE('F721',(#804),#779,.F.);
#806=CARTESIAN_POINT('',(60.,25.,135.));
#807=DIRECTION('',(0.,-1.,0.));
#808=DIRECTION('',(0.,0.,-1.));
#809=AXIS2_PLACEMENT_3D('',#806,#807,#808);
#810=PLANE('',#809);
#811=DIRECTION('',(0.,0.,1.));
#812=VECTOR('',#811,1.);
#813=CARTESIAN_POINT('',(60.,25.,135.));
#814=LINE('',#813,#812);
#815=CARTESIAN_POINT('',(60.,25.,105.));
#816=VERTEX_POINT('',#815);
#817=CARTESIAN_POINT('',(60.,25.,135.));
#818=VERTEX_POINT('',#817);
#819=EDGE_CURVE('E727',#816,#818,#814,.T.);
#820=ORIENTED_EDGE('',*,*,#819,.F.);
#821=DIRECTION('',(-1.,0.,0.));
#822=VECTOR('',#821,1.);
#823=CARTESIAN_POINT('',(50.,25.,105.));
#824=LINE('',#823,#822);
#825=CARTESIAN_POINT('',(50.,25.,105.));
#826=VERTEX_POINT('',#825);
#827=EDGE_CURVE('E753',#816,#826,#824,.T.);
#828=ORIENTED_EDGE('',*,*,#827,.T.);
#829=DIRECTION('',(0.,0.,1.));
#830=VECTOR('',#829,1.);
#831=CARTESIAN_POINT('',(50.,25.,135.));
#832=LINE('',#831,#830);
#833=CARTESIAN_POINT('',(50.,25.,135.));
#834=VERTEX_POINT('',#833);
#835=EDGE_CURVE('E794',#826,#834,#832,.T.);
#836=ORIENTED_EDGE('',*,*,#835,.T.);
#837=DIRECTION('',(-1.,0.,0.));
#838=VECTOR('',#837,1.);
#839=CARTESIAN_POINT('',(60.,25.,135.));
#840=LINE('',#839,#838);
#841=EDGE_CURVE('E742',#818,#834,#840,.T.);
#842=ORIENTED_EDGE('',*,*,#841,.F.);
#843=EDGE_LOOP('',(#820,#828,#836,#842));
#844=FACE_BOUND('',#843,.T.);
#845=ADVANCED_FACE('F819',(#844),#810,.F.);
#846=CARTESIAN_POINT('',(60.,-25.,135.));
#847=DIRECTION('',(0.,0.,-1.));
#848=DIRECTION('',(-1.,0.,0.));
#849=AXIS2_PLACEMENT_3D('',#846,#847,#848);
#850=PLANE('',#849);
#851=DIRECTION('',(0.,-1.,0.));
#852=VECTOR('',#851,1.);
#853=CARTESIAN_POINT('',(50.,-25.,135.));
#854=LINE('',#853,#852);
#855=CARTESIAN_POINT('',(50.,-25.,135.));
#856=VERTEX_POINT('',#855);
#857=EDGE_CURVE('E790',#834,#856,#854,.T.);
#858=ORIENTED_EDGE('',*,*,#857,.T.);
#859=DIRECTION('',(-1.,0.,0.));
#860=VECTOR('',#859,1.);
#861=CARTESIAN_POINT('',(60.,-25.,135.));
#862=LINE('',#861,#860);
#863=CARTESIAN_POINT('',(60.,-25.,135.));
#864=VERTEX_POINT('',#863);
#865=EDGE_CURVE('E748',#864,#856,#862,.T.);
#866=ORIENTED_EDGE('',*,*,#865,.F.);
#867=DIRECTION('',(0.,-1.,0.));
#868=VECTOR('',#867,1.);
#869=CARTESIAN_POINT('',(60.,-25.,135.));
#870=LINE('',#869,#868);
#871=EDGE_CURVE('E824',#818,#864,#870,.T.);
#872=ORIENTED_EDGE('',*,*,#871,.F.);
#873=ORIENTED_EDGE('',*,*,#841,.T.);
#874=EDGE_LOOP('',(#858,#866,#872,#873));
#875=FACE_BOUND('',#874,.T.);
#876=ADVANCED_FACE('F823',(#875),#850,.F.);
#877=CARTESIAN_POINT('',(60.,-25.,95.));
#878=DIRECTION('',(0.,1.,0.));
#879=DIRECTION('',(0.,0.,1.));
#880=AXIS2_PLACEMENT_3D('',#877,#878,#879);
#881=PLANE('',#880);
#882=DIRECTION('',(0.,0.,-1.));
#883=VECTOR('',#882,1.);
#884=CARTESIAN_POINT('',(50.,-25.,95.));
#885=LINE('',#884,#883);
#886=CARTESIAN_POINT('',(50.,-25.,105.));
#887=VERTEX_POINT('',#886);
#888=EDGE_CURVE('E783',#856,#887,#885,.T.);
#889=ORIENTED_EDGE('',*,*,#888,.T.);
#890=DIRECTION('',(-1.,0.,0.));
#891=VECTOR('',#890,1.);
#892=CARTESIAN_POINT('',(60.,-25.,105.));
#893=LINE('',#892,#891);
#894=CARTESIAN_POINT('',(60.,-25.,105.));
#895=VERTEX_POINT('',#894);
#896=EDGE_CURVE('E745',#887,#895,#893,.F.);
#897=ORIENTED_EDGE('',*,*,#896,.T.);
#898=DIRECTION('',(0.,0.,-1.));
#899=VECTOR('',#898,1.);
#900=CARTESIAN_POINT('',(60.,-25.,95.));
#901=LINE('',#900,#899);
#902=EDGE_CURVE('E766',#864,#895,#901,.T.);
#903=ORIENTED_EDGE('',*,*,#902,.F.);
#904=ORIENTED_EDGE('',*,*,#865,.T.);
#905=EDGE_LOOP('',(#889,#897,#903,#904));
#906=FACE_BOUND('',#905,.T.);
#907=ADVANCED_FACE('F788',(#906),#881,.F.);
#908=CARTESIAN_POINT('',(60.,-50.,35.));
#909=DIRECTION('',(0.,0.923076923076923,-0.384615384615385));
#910=DIRECTION('',(0.,0.384615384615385,0.923076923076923));
#911=AXIS2_PLACEMENT_3D('',#908,#909,#910);
#912=PLANE('',#911);
#913=DIRECTION('',(0.,-0.384615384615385,-0.923076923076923));
#914=VECTOR('',#913,1.);
#915=CARTESIAN_POINT('',(60.,-50.,35.));
#916=LINE('',#915,#914);
#917=CARTESIAN_POINT('',(60.,-28.8461538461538,85.7692307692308));
#918=VERTEX_POINT('',#917);
#919=CARTESIAN_POINT('',(60.,-50.,35.));
#920=VERTEX_POINT('',#919);
#921=EDGE_CURVE('E763',#918,#920,#916,.T.);
#922=ORIENTED_EDGE('',*,*,#921,.F.);
#923=DIRECTION('',(-1.,0.,0.));
#924=VECTOR('',#923,1.);
#925=CARTESIAN_POINT('',(50.,-28.8461538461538,85.7692307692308));
#926=LINE('',#925,#924);
#927=CARTESIAN_POINT('',(50.,-28.8461538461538,85.7692307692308));
#928=VERTEX_POINT('',#927);
#929=EDGE_CURVE('E741',#918,#928,#926,.T.);
#930=ORIENTED_EDGE('',*,*,#929,.T.);
#931=DIRECTION('',(0.,-0.384615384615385,-0.923076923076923));
#932=VECTOR('',#931,1.);
#933=CARTESIAN_POINT('',(50.,-50.,35.));
#934=LINE('',#933,#932);
#935=CARTESIAN_POINT('',(50.,-50.,35.));
#936=VERTEX_POINT('',#935);
#937=EDGE_CURVE('E785',#928,#936,#934,.T.);
#938=ORIENTED_EDGE('',*,*,#937,.T.);
#939=DIRECTION('',(-1.,0.,0.));
#940=VECTOR('',#939,1.);
#941=CARTESIAN_POINT('',(60.,-50.,35.));
#942=LINE('',#941,#940);
#943=EDGE_CURVE('E774',#920,#936,#942,.T.);
#944=ORIENTED_EDGE('',*,*,#943,.F.);
#945=EDGE_LOOP('',(#922,#930,#938,#944));
#946=FACE_BOUND('',#945,.T.);
#947=ADVANCED_FACE('F771',(#946),#912,.F.);
#948=CARTESIAN_POINT('',(60.,-50.,4.99999999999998));
#949=DIRECTION('',(0.,1.,0.));
#950=DIRECTION('',(0.,0.,1.));
#951=AXIS2_PLACEMENT_3D('',#948,#949,#950);
#952=PLANE('',#951);
#953=DIRECTION('',(0.,0.,-1.));
#954=VECTOR('',#953,1.);
#955=CARTESIAN_POINT('',(50.,-50.,4.99999999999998));
#956=LINE('',#955,#954);
#957=CARTESIAN_POINT('',(50.,-50.,4.99999999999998));
#958=VERTEX_POINT('',#957);
#959=EDGE_CURVE('E792',#936,#958,#956,.T.);
#960=ORIENTED_EDGE('',*,*,#959,.T.);
#961=DIRECTION('',(-1.,0.,0.));
#962=VECTOR('',#961,1.);
#963=CARTESIAN_POINT('',(60.,-50.,4.99999999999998));
#964=LINE('',#963,#962);
#965=CARTESIAN_POINT('',(60.,-50.,4.99999999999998));
#966=VERTEX_POINT('',#965);
#967=EDGE_CURVE('E802',#966,#958,#964,.T.);
#968=ORIENTED_EDGE('',*,*,#967,.F.);
#969=DIRECTION('',(0.,0.,-1.));
#970=VECTOR('',#969,1.);
#971=CARTESIAN_POINT('',(60.,-50.,4.99999999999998));
#972=LINE('',#971,#970);
#973=EDGE_CURVE('E776',#920,#966,#972,.T.);
#974=ORIENTED_EDGE('',*,*,#973,.F.);
#975=ORIENTED_EDGE('',*,*,#943,.T.);
#976=EDGE_LOOP('',(#960,#968,#974,#975));
#977=FACE_BOUND('',#976,.T.);
#978=ADVANCED_FACE('F806',(#977),#952,.F.);
#979=CARTESIAN_POINT('',(60.,50.,4.99999999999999));
#980=DIRECTION('',(0.,0.,1.));
#981=DIRECTION('',(0.,-1.,0.));
#982=AXIS2_PLACEMENT_3D('',#979,#980,#981);
#983=PLANE('',#982);
#984=DIRECTION('',(0.,1.,0.));
#985=VECTOR('',#984,1.);
#986=CARTESIAN_POINT('',(50.,50.,4.99999999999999));
#987=LINE('',#986,#985);
#988=EDGE_CURVE('E737',#958,#745,#987,.T.);
#989=ORIENTED_EDGE('',*,*,#988,.T.);
#990=ORIENTED_EDGE('',*,*,#770,.F.);
#991=DIRECTION('',(0.,1.,0.));
#992=VECTOR('',#991,1.);
#993=CARTESIAN_POINT('',(60.,50.,4.99999999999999));
#994=LINE('',#993,#992);
#995=EDGE_CURVE('E733',#966,#763,#994,.T.);
#996=ORIENTED_EDGE('',*,*,#995,.F.);
#997=ORIENTED_EDGE('',*,*,#967,.T.);
#998=EDGE_LOOP('',(#989,#990,#996,#997));
#999=FACE_BOUND('',#998,.T.);
#1000=ADVANCED_FACE('F810',(#999),#983,.F.);
#1001=CARTESIAN_POINT('',(60.,0.,0.));
#1002=DIRECTION('',(-1.,0.,0.));
#1003=DIRECTION('',(0.,0.,1.));
#1004=AXIS2_PLACEMENT_3D('',#1001,#1002,#1003);
#1005=PLANE('',#1004);
#1006=ORIENTED_EDGE('',*,*,#764,.T.);
#1007=ORIENTED_EDGE('',*,*,#800,.T.);
#1008=CARTESIAN_POINT('',(60.,75.,105.));
#1009=DIRECTION('',(-1.,0.,0.));
#1010=DIRECTION('',(0.,0.,1.));
#1011=AXIS2_PLACEMENT_3D('',#1008,#1009,#1010);
#1012=CIRCLE('',#1011,50.);
#1013=EDGE_CURVE('E356',#793,#816,#1012,.T.);
#1014=ORIENTED_EDGE('',*,*,#1013,.T.);
#1015=ORIENTED_EDGE('',*,*,#819,.T.);
#1016=ORIENTED_EDGE('',*,*,#871,.T.);
#1017=ORIENTED_EDGE('',*,*,#902,.T.);
#1018=CARTESIAN_POINT('',(60.,-75.,105.));
#1019=DIRECTION('',(-1.,0.,0.));
#1020=DIRECTION('',(0.,0.,1.));
#1021=AXIS2_PLACEMENT_3D('',#1018,#1019,#1020);
#1022=CIRCLE('',#1021,50.);
#1023=EDGE_CURVE('E759',#895,#918,#1022,.T.);
#1024=ORIENTED_EDGE('',*,*,#1023,.T.);
#1025=ORIENTED_EDGE('',*,*,#921,.T.);
#1026=ORIENTED_EDGE('',*,*,#973,.T.);
#1027=ORIENTED_EDGE('',*,*,#995,.T.);
#1028=EDGE_LOOP('',(#1006,#1007,#1014,#1015,#1016,#1017,#1024,#1025,#1026,#1027));
#1029=FACE_BOUND('',#1028,.T.);
#1030=ADVANCED_FACE('F731',(#1029),#1005,.F.);
#1031=CARTESIAN_POINT('',(50.,0.,0.));
#1032=DIRECTION('',(-1.,0.,0.));
#1033=DIRECTION('',(0.,0.,1.));
#1034=AXIS2_PLACEMENT_3D('',#1031,#1032,#1033);
#1035=PLANE('',#1034);
#1036=ORIENTED_EDGE('',*,*,#748,.F.);
#1037=ORIENTED_EDGE('',*,*,#988,.F.);
#1038=ORIENTED_EDGE('',*,*,#959,.F.);
#1039=ORIENTED_EDGE('',*,*,#937,.F.);
#1040=CARTESIAN_POINT('',(50.,-75.,105.));
#1041=DIRECTION('',(-1.,0.,0.));
#1042=DIRECTION('',(0.,0.,1.));
#1043=AXIS2_PLACEMENT_3D('',#1040,#1041,#1042);
#1044=CIRCLE('',#1043,50.);
#1045=EDGE_CURVE('E757',#928,#887,#1044,.F.);
#1046=ORIENTED_EDGE('',*,*,#1045,.T.);
#1047=ORIENTED_EDGE('',*,*,#888,.F.);
#1048=ORIENTED_EDGE('',*,*,#857,.F.);
#1049=ORIENTED_EDGE('',*,*,#835,.F.);
#1050=CARTESIAN_POINT('',(50.,75.,105.));
#1051=DIRECTION('',(-1.,0.,0.));
#1052=DIRECTION('',(0.,0.,1.));
#1053=AXIS2_PLACEMENT_3D('',#1050,#1051,#1052);
#1054=CIRCLE('',#1053,50.);
#1055=EDGE_CURVE('E654',#826,#785,#1054,.F.);
#1056=ORIENTED_EDGE('',*,*,#1055,.T.);
#1057=ORIENTED_EDGE('',*,*,#786,.F.);
#1058=EDGE_LOOP('',(#1036,#1037,#1038,#1039,#1046,#1047,#1048,#1049,#1056,#1057));
#1059=FACE_BOUND('',#1058,.T.);
#1060=ADVANCED_FACE('F781',(#1059),#1035,.T.);
#1061=CARTESIAN_POINT('',(60.,-75.,105.));
#1062=DIRECTION('',(1.,0.,0.));
#1063=DIRECTION('',(0.,0.,-1.));
#1064=AXIS2_PLACEMENT_3D('',#1061,#1062,#1063);
#1065=CYLINDRICAL_SURFACE('',#1064,50.);
#1066=ORIENTED_EDGE('',*,*,#1023,.F.);
#1067=ORIENTED_EDGE('',*,*,#896,.F.);
#1068=ORIENTED_EDGE('',*,*,#1045,.F.);
#1069=ORIENTED_EDGE('',*,*,#929,.F.);
#1070=EDGE_LOOP('',(#1066,#1067,#1068,#1069));
#1071=FACE_BOUND('',#1070,.T.);
#1072=ADVANCED_FACE('F778',(#1071),#1065,.F.);
#1073=CARTESIAN_POINT('',(60.,75.,105.));
#1074=DIRECTION('',(1.,0.,0.));
#1075=DIRECTION('',(0.,0.,-1.));
#1076=AXIS2_PLACEMENT_3D('',#1073,#1074,#1075);
#1077=CYLINDRICAL_SURFACE('',#1076,50.);
#1078=ORIENTED_EDGE('',*,*,#1013,.F.);
#1079=ORIENTED_EDGE('',*,*,#794,.F.);
#1080=ORIENTED_EDGE('',*,*,#1055,.F.);
#1081=ORIENTED_EDGE('',*,*,#827,.F.);
#1082=EDGE_LOOP('',(#1078,#1079,#1080,#1081));
#1083=FACE_BOUND('',#1082,.T.);
#1084=ADVANCED_FACE('F648',(#1083),#1077,.F.);
#1085=CLOSED_SHELL('',(#774,#805,#845,#876,#907,#947,#978,#1000,#1030,#1060,#1072,#1084));
#1086=MANIFOLD_SOLID_BREP('B196',#1085);
#1087=CARTESIAN_POINT('',(50.,50.,0.));
#1088=DIRECTION('',(0.,0.,1.));
#1089=DIRECTION('',(1.,0.,0.));
#1090=AXIS2_PLACEMENT_3D('',#1087,#1088,#1089);
#1091=PLANE('',#1090);
#1092=CARTESIAN_POINT('',(28.284271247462,-28.2842712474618,0.));
#1093=DIRECTION('',(0.,0.,-1.));
#1094=DIRECTION('',(-1.,0.,0.));
#1095=AXIS2_PLACEMENT_3D('',#1092,#1093,#1094);
#1096=CIRCLE('',#1095,4.49999999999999);
#1097=CARTESIAN_POINT('',(23.784271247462,-28.2842712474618,0.));
#1098=VERTEX_POINT('',#1097);
#1099=EDGE_CURVE('E1041',#1098,#1098,#1096,.T.);
#1100=ORIENTED_EDGE('',*,*,#1099,.F.);
#1101=EDGE_LOOP('',(#1100));
#1102=FACE_BOUND('',#1101,.T.);
#1103=CARTESIAN_POINT('',(-28.2842712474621,-28.2842712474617,0.));
#1104=DIRECTION('',(0.,0.,-1.));
#1105=DIRECTION('',(-1.,0.,0.));
#1106=AXIS2_PLACEMENT_3D('',#1103,#1104,#1105);
#1107=CIRCLE('',#1106,4.49999999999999);
#1108=CARTESIAN_POINT('',(-32.784271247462,-28.2842712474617,0.));
#1109=VERTEX_POINT('',#1108);
#1110=EDGE_CURVE('E1035',#1109,#1109,#1107,.T.);
#1111=ORIENTED_EDGE('',*,*,#1110,.F.);
#1112=EDGE_LOOP('',(#1111));
#1113=FACE_BOUND('',#1112,.T.);
#1114=CARTESIAN_POINT('',(-28.2842712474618,28.284271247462,0.));
#1115=DIRECTION('',(0.,0.,-1.));
#1116=DIRECTION('',(-1.,0.,0.));
#1117=AXIS2_PLACEMENT_3D('',#1114,#1115,#1116);
#1118=CIRCLE('',#1117,4.49999999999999);
#1119=CARTESIAN_POINT('',(-32.7842712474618,28.284271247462,0.));
#1120=VERTEX_POINT('',#1119);
#1121=EDGE_CURVE('E1029',#1120,#1120,#1118,.T.);
#1122=ORIENTED_EDGE('',*,*,#1121,.F.);
#1123=EDGE_LOOP('',(#1122));
#1124=FACE_BOUND('',#1123,.T.);
#1125=CARTESIAN_POINT('',(-35.,0.,0.));
#1126=DIRECTION('',(0.,0.,-1.));
#1127=DIRECTION('',(-1.,0.,0.));
#1128=AXIS2_PLACEMENT_3D('',#1125,#1126,#1127);
#1129=CIRCLE('',#1128,4.00000000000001);
#1130=CARTESIAN_POINT('',(-39.,0.,0.));
#1131=VERTEX_POINT('',#1130);
#1132=EDGE_CURVE('E1012',#1131,#1131,#1129,.T.);
#1133=ORIENTED_EDGE('',*,*,#1132,.F.);
#1134=EDGE_LOOP('',(#1133));
#1135=FACE_BOUND('',#1134,.T.);
#1136=CARTESIAN_POINT('',(35.,0.,0.));
#1137=DIRECTION('',(0.,0.,-1.));
#1138=DIRECTION('',(-1.,0.,0.));
#1139=AXIS2_PLACEMENT_3D('',#1136,#1137,#1138);
#1140=CIRCLE('',#1139,4.);
#1141=CARTESIAN_POINT('',(31.,0.,0.));
#1142=VERTEX_POINT('',#1141);
#1143=EDGE_CURVE('E1013',#1142,#1142,#1140,.T.);
#1144=ORIENTED_EDGE('',*,*,#1143,.F.);
#1145=EDGE_LOOP('',(#1144));
#1146=FACE_BOUND('',#1145,.T.);
#1147=CARTESIAN_POINT('',(0.,0.,0.));
#1148=DIRECTION('',(0.,0.,-1.));
#1149=DIRECTION('',(-1.,0.,0.));
#1150=AXIS2_PLACEMENT_3D('',#1147,#1148,#1149);
#1151=CIRCLE('',#1150,25.);
#1152=CARTESIAN_POINT('',(-25.,0.,0.));
#1153=VERTEX_POINT('',#1152);
#1154=EDGE_CURVE('E644',#1153,#1153,#1151,.T.);
#1155=ORIENTED_EDGE('',*,*,#1154,.F.);
#1156=EDGE_LOOP('',(#1155));
#1157=FACE_BOUND('',#1156,.T.);
#1158=DIRECTION('',(0.,1.,0.));
#1159=VECTOR('',#1158,1.);
#1160=CARTESIAN_POINT('',(-50.,50.,0.));
#1161=LINE('',#1160,#1159);
#1162=CARTESIAN_POINT('',(-50.,-50.,0.));
#1163=VERTEX_POINT('',#1162);
#1164=CARTESIAN_POINT('',(-50.,50.,0.));
#1165=VERTEX_POINT('',#1164);
#1166=EDGE_CURVE('E960',#1163,#1165,#1161,.T.);
#1167=ORIENTED_EDGE('',*,*,#1166,.T.);
#1168=DIRECTION('',(-1.,0.,0.));
#1169=VECTOR('',#1168,1.);
#1170=CARTESIAN_POINT('',(50.,50.,0.));
#1171=LINE('',#1170,#1169);
#1172=CARTESIAN_POINT('',(50.,50.,0.));
#1173=VERTEX_POINT('',#1172);
#1174=EDGE_CURVE('E985',#1173,#1165,#1171,.T.);
#1175=ORIENTED_EDGE('',*,*,#1174,.F.);
#1176=DIRECTION('',(0.,1.,0.));
#1177=VECTOR('',#1176,1.);
#1178=CARTESIAN_POINT('',(50.,50.,0.));
#1179=LINE('',#1178,#1177);
#1180=CARTESIAN_POINT('',(50.,-50.,0.));
#1181=VERTEX_POINT('',#1180);
#1182=EDGE_CURVE('E977',#1181,#1173,#1179,.T.);
#1183=ORIENTED_EDGE('',*,*,#1182,.F.);
#1184=DIRECTION('',(-1.,0.,0.));
#1185=VECTOR('',#1184,1.);
#1186=CARTESIAN_POINT('',(50.,-50.,0.));
#1187=LINE('',#1186,#1185);
#1188=EDGE_CURVE('E982',#1181,#1163,#1187,.T.);
#1189=ORIENTED_EDGE('',*,*,#1188,.T.);
#1190=EDGE_LOOP('',(#1167,#1175,#1183,#1189));
#1191=FACE_BOUND('',#1190,.T.);
#1192=CARTESIAN_POINT('',(28.2842712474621,28.2842712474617,0.));
#1193=DIRECTION('',(0.,0.,-1.));
#1194=DIRECTION('',(-1.,0.,0.));
#1195=AXIS2_PLACEMENT_3D('',#1192,#1193,#1194);
#1196=CIRCLE('',#1195,4.49999999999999);
#1197=CARTESIAN_POINT('',(23.7842712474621,28.2842712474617,0.));
#1198=VERTEX_POINT('',#1197);
#1199=EDGE_CURVE('E1023',#1198,#1198,#1196,.T.);
#1200=ORIENTED_EDGE('',*,*,#1199,.F.);
#1201=EDGE_LOOP('',(#1200));
#1202=FACE_BOUND('',#1201,.T.);
#1203=ADVANCED_FACE('F925',(#1102,#1113,#1124,#1135,#1146,#1157,#1191,#1202),#1091,.F.);
#1204=CARTESIAN_POINT('',(50.,50.,15.));
#1205=DIRECTION('',(0.,0.,-1.));
#1206=DIRECTION('',(-1.,0.,0.));
#1207=AXIS2_PLACEMENT_3D('',#1204,#1205,#1206);
#1208=PLANE('',#1207);
#1209=CARTESIAN_POINT('',(28.284271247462,-28.2842712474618,15.));
#1210=DIRECTION('',(0.,0.,-1.));
#1211=DIRECTION('',(-1.,0.,0.));
#1212=AXIS2_PLACEMENT_3D('',#1209,#1210,#1211);
#1213=CIRCLE('',#1212,4.49999999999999);
#1214=CARTESIAN_POINT('',(23.784271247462,-28.2842712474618,15.));
#1215=VERTEX_POINT('',#1214);
#1216=EDGE_CURVE('E1038',#1215,#1215,#1213,.T.);
#1217=ORIENTED_EDGE('',*,*,#1216,.T.);
#1218=EDGE_LOOP('',(#1217));
#1219=FACE_BOUND('',#1218,.T.);
#1220=CARTESIAN_POINT('',(-28.2842712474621,-28.2842712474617,15.));
#1221=DIRECTION('',(0.,0.,-1.));
#1222=DIRECTION('',(-1.,0.,0.));
#1223=AXIS2_PLACEMENT_3D('',#1220,#1221,#1222);
#1224=CIRCLE('',#1223,4.49999999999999);
#1225=CARTESIAN_POINT('',(-32.784271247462,-28.2842712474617,15.));
#1226=VERTEX_POINT('',#1225);
#1227=EDGE_CURVE('E1032',#1226,#1226,#1224,.T.);
#1228=ORIENTED_EDGE('',*,*,#1227,.T.);
#1229=EDGE_LOOP('',(#1228));
#1230=FACE_BOUND('',#1229,.T.);
#1231=CARTESIAN_POINT('',(-28.2842712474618,28.284271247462,15.));
#1232=DIRECTION('',(0.,0.,-1.));
#1233=DIRECTION('',(-1.,0.,0.));
#1234=AXIS2_PLACEMENT_3D('',#1231,#1232,#1233);
#1235=CIRCLE('',#1234,4.49999999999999);
#1236=CARTESIAN_POINT('',(-32.7842712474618,28.284271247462,15.));
#1237=VERTEX_POINT('',#1236);
#1238=EDGE_CURVE('E1026',#1237,#1237,#1235,.T.);
#1239=ORIENTED_EDGE('',*,*,#1238,.T.);
#1240=EDGE_LOOP('',(#1239));
#1241=FACE_BOUND('',#1240,.T.);
#1242=CARTESIAN_POINT('',(28.2842712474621,28.2842712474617,15.));
#1243=DIRECTION('',(0.,0.,-1.));
#1244=DIRECTION('',(-1.,0.,0.));
#1245=AXIS2_PLACEMENT_3D('',#1242,#1243,#1244);
#1246=CIRCLE('',#1245,4.49999999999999);
#1247=CARTESIAN_POINT('',(23.7842712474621,28.2842712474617,15.));
#1248=VERTEX_POINT('',#1247);
#1249=EDGE_CURVE('E1016',#1248,#1248,#1246,.T.);
#1250=ORIENTED_EDGE('',*,*,#1249,.T.);
#1251=EDGE_LOOP('',(#1250));
#1252=FACE_BOUND('',#1251,.T.);
#1253=CARTESIAN_POINT('',(-35.,0.,15.));
#1254=DIRECTION('',(0.,0.,-1.));
#1255=DIRECTION('',(-1.,0.,0.));
#1256=AXIS2_PLACEMENT_3D('',#1253,#1254,#1255);
#1257=CIRCLE('',#1256,4.00000000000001);
#1258=CARTESIAN_POINT('',(-39.,0.,15.));
#1259=VERTEX_POINT('',#1258);
#1260=EDGE_CURVE('E1008',#1259,#1259,#1257,.F.);
#1261=ORIENTED_EDGE('',*,*,#1260,.F.);
#1262=EDGE_LOOP('',(#1261));
#1263=FACE_BOUND('',#1262,.T.);
#1264=CARTESIAN_POINT('',(35.,0.,15.));
#1265=DIRECTION('',(0.,0.,-1.));
#1266=DIRECTION('',(-1.,0.,0.));
#1267=AXIS2_PLACEMENT_3D('',#1264,#1265,#1266);
#1268=CIRCLE('',#1267,4.);
#1269=CARTESIAN_POINT('',(31.,0.,15.));
#1270=VERTEX_POINT('',#1269);
#1271=EDGE_CURVE('E1009',#1270,#1270,#1268,.F.);
#1272=ORIENTED_EDGE('',*,*,#1271,.F.);
#1273=EDGE_LOOP('',(#1272));
#1274=FACE_BOUND('',#1273,.T.);
#1275=DIRECTION('',(0.,-1.,0.));
#1276=VECTOR('',#1275,1.);
#1277=CARTESIAN_POINT('',(-50.,50.,15.));
#1278=LINE('',#1277,#1276);
#1279=CARTESIAN_POINT('',(-50.,50.,15.));
#1280=VERTEX_POINT('',#1279);
#1281=CARTESIAN_POINT('',(-50.,-50.,15.));
#1282=VERTEX_POINT('',#1281);
#1283=EDGE_CURVE('E992',#1280,#1282,#1278,.T.);
#1284=ORIENTED_EDGE('',*,*,#1283,.T.);
#1285=DIRECTION('',(-1.,0.,0.));
#1286=VECTOR('',#1285,1.);
#1287=CARTESIAN_POINT('',(50.,-50.,15.));
#1288=LINE('',#1287,#1286);
#1289=CARTESIAN_POINT('',(50.,-50.,15.));
#1290=VERTEX_POINT('',#1289);
#1291=EDGE_CURVE('E929',#1290,#1282,#1288,.T.);
#1292=ORIENTED_EDGE('',*,*,#1291,.F.);
#1293=DIRECTION('',(0.,-1.,0.));
#1294=VECTOR('',#1293,1.);
#1295=CARTESIAN_POINT('',(50.,50.,15.));
#1296=LINE('',#1295,#1294);
#1297=CARTESIAN_POINT('',(50.,50.,15.));
#1298=VERTEX_POINT('',#1297);
#1299=EDGE_CURVE('E979',#1298,#1290,#1296,.T.);
#1300=ORIENTED_EDGE('',*,*,#1299,.F.);
#1301=DIRECTION('',(-1.,0.,0.));
#1302=VECTOR('',#1301,1.);
#1303=CARTESIAN_POINT('',(50.,50.,15.));
#1304=LINE('',#1303,#1302);
#1305=EDGE_CURVE('E988',#1298,#1280,#1304,.T.);
#1306=ORIENTED_EDGE('',*,*,#1305,.T.);
#1307=EDGE_LOOP('',(#1284,#1292,#1300,#1306));
#1308=FACE_BOUND('',#1307,.T.);
#1309=ADVANCED_FACE('F927',(#1219,#1230,#1241,#1252,#1263,#1274,#1308),#1208,.F.);
#1310=CARTESIAN_POINT('',(50.,-50.,15.));
#1311=DIRECTION('',(0.,1.,0.));
#1312=DIRECTION('',(0.,0.,1.));
#1313=AXIS2_PLACEMENT_3D('',#1310,#1311,#1312);
#1314=PLANE('',#1313);
#1315=DIRECTION('',(0.,0.,-1.));
#1316=VECTOR('',#1315,1.);
#1317=CARTESIAN_POINT('',(-50.,-50.,15.));
#1318=LINE('',#1317,#1316);
#1319=EDGE_CURVE('E984',#1282,#1163,#1318,.T.);
#1320=ORIENTED_EDGE('',*,*,#1319,.T.);
#1321=ORIENTED_EDGE('',*,*,#1188,.F.);
#1322=DIRECTION('',(0.,0.,-1.));
#1323=VECTOR('',#1322,1.);
#1324=CARTESIAN_POINT('',(50.,-50.,15.));
#1325=LINE('',#1324,#1323);
#1326=EDGE_CURVE('E974',#1290,#1181,#1325,.T.);
#1327=ORIENTED_EDGE('',*,*,#1326,.F.);
#1328=ORIENTED_EDGE('',*,*,#1291,.T.);
#1329=EDGE_LOOP('',(#1320,#1321,#1327,#1328));
#1330=FACE_BOUND('',#1329,.T.);
#1331=ADVANCED_FACE('F983',(#1330),#1314,.F.);
#1332=CARTESIAN_POINT('',(50.,50.,15.));
#1333=DIRECTION('',(0.,-1.,0.));
#1334=DIRECTION('',(0.,0.,-1.));
#1335=AXIS2_PLACEMENT_3D('',#1332,#1333,#1334);
#1336=PLANE('',#1335);
#1337=DIRECTION('',(0.,0.,1.));
#1338=VECTOR('',#1337,1.);
#1339=CARTESIAN_POINT('',(-50.,50.,15.));
#1340=LINE('',#1339,#1338);
#1341=EDGE_CURVE('E966',#1165,#1280,#1340,.T.);
#1342=ORIENTED_EDGE('',*,*,#1341,.T.);
#1343=ORIENTED_EDGE('',*,*,#1305,.F.);
#1344=DIRECTION('',(0.,0.,1.));
#1345=VECTOR('',#1344,1.);
#1346=CARTESIAN_POINT('',(50.,50.,15.));
#1347=LINE('',#1346,#1345);
#1348=EDGE_CURVE('E943',#1173,#1298,#1347,.T.);
#1349=ORIENTED_EDGE('',*,*,#1348,.F.);
#1350=ORIENTED_EDGE('',*,*,#1174,.T.);
#1351=EDGE_LOOP('',(#1342,#1343,#1349,#1350));
#1352=FACE_BOUND('',#1351,.T.);
#1353=ADVANCED_FACE('F1000',(#1352),#1336,.F.);
#1354=CARTESIAN_POINT('',(50.,0.,0.));
#1355=DIRECTION('',(1.,0.,0.));
#1356=DIRECTION('',(0.,0.,-1.));
#1357=AXIS2_PLACEMENT_3D('',#1354,#1355,#1356);
#1358=PLANE('',#1357);
#1359=ORIENTED_EDGE('',*,*,#1299,.T.);
#1360=ORIENTED_EDGE('',*,*,#1326,.T.);
#1361=ORIENTED_EDGE('',*,*,#1182,.T.);
#1362=ORIENTED_EDGE('',*,*,#1348,.T.);
#1363=EDGE_LOOP('',(#1359,#1360,#1361,#1362));
#1364=FACE_BOUND('',#1363,.T.);
#1365=ADVANCED_FACE('F975',(#1364),#1358,.T.);
#1366=CARTESIAN_POINT('',(-50.,0.,0.));
#1367=DIRECTION('',(1.,0.,0.));
#1368=DIRECTION('',(0.,0.,-1.));
#1369=AXIS2_PLACEMENT_3D('',#1366,#1367,#1368);
#1370=PLANE('',#1369);
#1371=ORIENTED_EDGE('',*,*,#1283,.F.);
#1372=ORIENTED_EDGE('',*,*,#1341,.F.);
#1373=ORIENTED_EDGE('',*,*,#1166,.F.);
#1374=ORIENTED_EDGE('',*,*,#1319,.F.);
#1375=EDGE_LOOP('',(#1371,#1372,#1373,#1374));
#1376=FACE_BOUND('',#1375,.T.);
#1377=ADVANCED_FACE('F1003',(#1376),#1370,.F.);
#1378=CARTESIAN_POINT('',(0.,0.,-5.));
#1379=DIRECTION('',(0.,0.,1.));
#1380=DIRECTION('',(1.,0.,0.));
#1381=AXIS2_PLACEMENT_3D('',#1378,#1379,#1380);
#1382=CYLINDRICAL_SURFACE('',#1381,25.);
#1383=CARTESIAN_POINT('',(0.,0.,-5.));
#1384=DIRECTION('',(0.,0.,-1.));
#1385=DIRECTION('',(-1.,0.,0.));
#1386=AXIS2_PLACEMENT_3D('',#1383,#1384,#1385);
#1387=CIRCLE('',#1386,25.);
#1388=CARTESIAN_POINT('',(-25.,0.,-5.));
#1389=VERTEX_POINT('',#1388);
#1390=EDGE_CURVE('E995',#1389,#1389,#1387,.T.);
#1391=ORIENTED_EDGE('',*,*,#1390,.F.);
#1392=EDGE_LOOP('',(#1391));
#1393=FACE_BOUND('',#1392,.T.);
#1394=ORIENTED_EDGE('',*,*,#1154,.T.);
#1395=EDGE_LOOP('',(#1394));
#1396=FACE_BOUND('',#1395,.T.);
#1397=ADVANCED_FACE('F1060',(#1393,#1396),#1382,.T.);
#1398=CARTESIAN_POINT('',(0.,0.,-5.));
#1399=DIRECTION('',(0.,0.,-1.));
#1400=DIRECTION('',(-1.,0.,0.));
#1401=AXIS2_PLACEMENT_3D('',#1398,#1399,#1400);
#1402=PLANE('',#1401);
#1403=ORIENTED_EDGE('',*,*,#1390,.T.);
#1404=EDGE_LOOP('',(#1403));
#1405=FACE_BOUND('',#1404,.T.);
#1406=ADVANCED_FACE('F1062',(#1405),#1402,.T.);
#1407=CARTESIAN_POINT('',(35.,0.,230.001));
#1408=DIRECTION('',(0.,0.,-1.));
#1409=DIRECTION('',(-1.,0.,0.));
#1410=AXIS2_PLACEMENT_3D('',#1407,#1408,#1409);
#1411=CYLINDRICAL_SURFACE('',#1410,4.);
#1412=ORIENTED_EDGE('',*,*,#1143,.T.);
#1413=EDGE_LOOP('',(#1412));
#1414=FACE_BOUND('',#1413,.T.);
#1415=ORIENTED_EDGE('',*,*,#1271,.T.);
#1416=EDGE_LOOP('',(#1415));
#1417=FACE_BOUND('',#1416,.T.);
#1418=ADVANCED_FACE('F1069',(#1414,#1417),#1411,.F.);
#1419=CARTESIAN_POINT('',(-35.,0.,230.001));
#1420=DIRECTION('',(0.,0.,-1.));
#1421=DIRECTION('',(-1.,0.,0.));
#1422=AXIS2_PLACEMENT_3D('',#1419,#1420,#1421);
#1423=CYLINDRICAL_SURFACE('',#1422,4.00000000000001);
#1424=ORIENTED_EDGE('',*,*,#1132,.T.);
#1425=EDGE_LOOP('',(#1424));
#1426=FACE_BOUND('',#1425,.T.);
#1427=ORIENTED_EDGE('',*,*,#1260,.T.);
#1428=EDGE_LOOP('',(#1427));
#1429=FACE_BOUND('',#1428,.T.);
#1430=ADVANCED_FACE('F1099',(#1426,#1429),#1423,.F.);
#1431=CARTESIAN_POINT('',(28.2842712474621,28.2842712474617,0.));
#1432=DIRECTION('',(0.,0.,-1.));
#1433=DIRECTION('',(-1.,0.,0.));
#1434=AXIS2_PLACEMENT_3D('',#1431,#1432,#1433);
#1435=CYLINDRICAL_SURFACE('',#1434,4.49999999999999);
#1436=ORIENTED_EDGE('',*,*,#1249,.F.);
#1437=EDGE_LOOP('',(#1436));
#1438=FACE_BOUND('',#1437,.T.);
#1439=ORIENTED_EDGE('',*,*,#1199,.T.);
#1440=EDGE_LOOP('',(#1439));
#1441=FACE_BOUND('',#1440,.T.);
#1442=ADVANCED_FACE('F1104',(#1438,#1441),#1435,.F.);
#1443=CARTESIAN_POINT('',(-28.2842712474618,28.284271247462,0.));
#1444=DIRECTION('',(0.,0.,-1.));
#1445=DIRECTION('',(-1.,0.,0.));
#1446=AXIS2_PLACEMENT_3D('',#1443,#1444,#1445);
#1447=CYLINDRICAL_SURFACE('',#1446,4.49999999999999);
#1448=ORIENTED_EDGE('',*,*,#1238,.F.);
#1449=EDGE_LOOP('',(#1448));
#1450=FACE_BOUND('',#1449,.T.);
#1451=ORIENTED_EDGE('',*,*,#1121,.T.);
#1452=EDGE_LOOP('',(#1451));
#1453=FACE_BOUND('',#1452,.T.);
#1454=ADVANCED_FACE('F1110',(#1450,#1453),#1447,.F.);
#1455=CARTESIAN_POINT('',(-28.2842712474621,-28.2842712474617,0.));
#1456=DIRECTION('',(0.,0.,-1.));
#1457=DIRECTION('',(-1.,0.,0.));
#1458=AXIS2_PLACEMENT_3D('',#1455,#1456,#1457);
#1459=CYLINDRICAL_SURFACE('',#1458,4.49999999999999);
#1460=ORIENTED_EDGE('',*,*,#1227,.F.);
#1461=EDGE_LOOP('',(#1460));
#1462=FACE_BOUND('',#1461,.T.);
#1463=ORIENTED_EDGE('',*,*,#1110,.T.);
#1464=EDGE_LOOP('',(#1463));
#1465=FACE_BOUND('',#1464,.T.);
#1466=ADVANCED_FACE('F1114',(#1462,#1465),#1459,.F.);
#1467=CARTESIAN_POINT('',(28.284271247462,-28.2842712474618,0.));
#1468=DIRECTION('',(0.,0.,-1.));
#1469=DIRECTION('',(-1.,0.,0.));
#1470=AXIS2_PLACEMENT_3D('',#1467,#1468,#1469);
#1471=CYLINDRICAL_SURFACE('',#1470,4.49999999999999);
#1472=ORIENTED_EDGE('',*,*,#1216,.F.);
#1473=EDGE_LOOP('',(#1472));
#1474=FACE_BOUND('',#1473,.T.);
#1475=ORIENTED_EDGE('',*,*,#1099,.T.);
#1476=EDGE_LOOP('',(#1475));
#1477=FACE_BOUND('',#1476,.T.);
#1478=ADVANCED_FACE('F1045',(#1474,#1477),#1471,.F.);
#1479=CLOSED_SHELL('',(#1203,#1309,#1331,#1353,#1365,#1377,#1397,#1406,#1418,#1430,#1442,#1454,
#1466,#1478));
#1480=MANIFOLD_SOLID_BREP('B350',#1479);
#1481=ADVANCED_BREP_SHAPE_REPRESENTATION('',(#18,#86,#198,#382,#734,#1086,#1480),#14);
#1482=SHAPE_DEFINITION_REPRESENTATION(#9,#1481);
ENDSEC;
END-ISO-10303-21;
